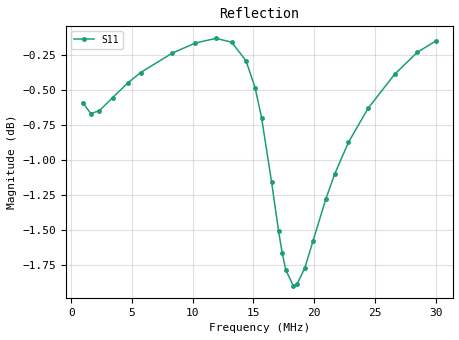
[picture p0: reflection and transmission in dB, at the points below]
! ListType=Log
# MHz S RI R 50
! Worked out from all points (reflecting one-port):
!   200 points, 1 MHz to 30 MHz, reference 50 ohm
!   lowest |S11| = -1.9 dB at 18.28 MHz (marker M1), VSWR 9.19, Z = 6.13 + j17.7 ohm
!   phase of S11 starts at 132 deg and turns -525 deg over the sweep
!   S11 on the Smith chart (normalised r, x): 1 MHz: 0.04, +0.45; 5.716 MHz: 0.34, +3.84; 14.39 MHz: 0.05, -1.35; 17.36 MHz: 0.10, -0.01; 20.95 MHz: 0.27, +1.60; 30 MHz: 0.11, -3.37
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1  -0.6202 0.698
1.61375  -0.2933 0.8783
2.310539  0.0448 0.927
3.423228  0.4401 0.8286
4.656341  0.7038 0.6374
5.716332  0.8379 0.4639
8.325633  0.9716 0.0553
10.22092  0.9509 -0.2424
11.9205  0.8298 -0.5308
13.20781  0.6237 -0.7584
14.38614  0.283 -0.9248
15.14302  -0.0367 -0.9449
15.6696  -0.2946 -0.8745
16.494  -0.6691 -0.5642
17.06756  -0.8122 -0.2166
17.36178  -0.8256 -0.0204
17.66107  -0.7953 0.1744
18.27521  -0.6208 0.5104
18.59024  -0.4939 0.6352
19.2367  -0.211 0.788
19.90563  0.0612 0.8316
20.9529  0.3924 0.7686
21.68151  0.5572 0.6823
22.82221  0.7361 0.5254
24.43704  0.8814 0.2967
26.61719  0.9563 -0.0104
28.50054  0.9296 -0.2905
30  0.8242 -0.5355
